# Generated by innovus_enablement/scripts/gen_fakeram.py: abstract 256x32 SRAM.
# Geometry is an assumption (see script header), not PDK data.
VERSION 5.8 ;
BUSBITCHARS "[]" ;
DIVIDERCHAR "/" ;

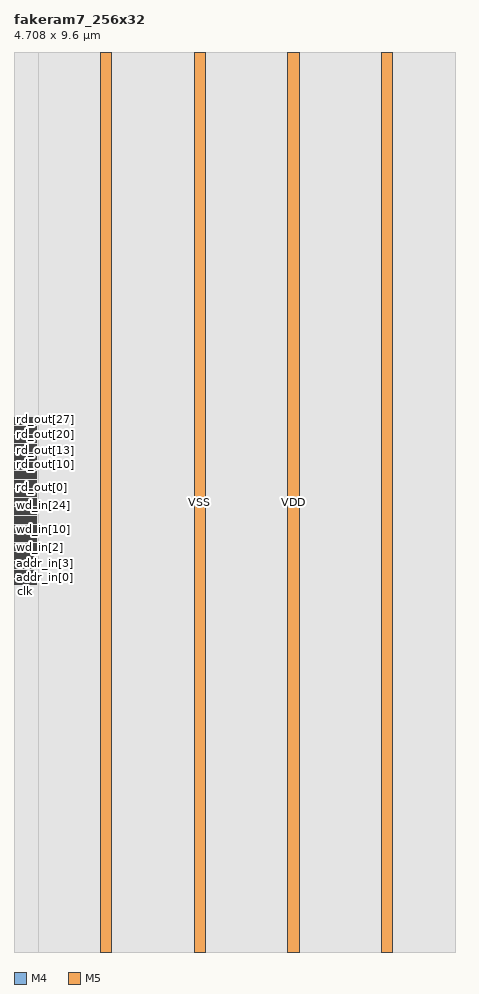
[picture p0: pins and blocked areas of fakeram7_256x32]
MACRO fakeram7_256x32
  CLASS BLOCK ;
  FOREIGN fakeram7_256x32 0 0 ;
  ORIGIN 0 0 ;
  SIZE 4.7080 BY 9.6000 ;
  SYMMETRY X Y R90 ;
  PIN clk
    DIRECTION INPUT ;
    USE CLOCK ;
    PORT
      LAYER M4 ;
        RECT 0 3.9180 0.2400 3.9300 ;
    END
  END clk
  PIN ce_in
    DIRECTION INPUT ;
    USE SIGNAL ;
    PORT
      LAYER M4 ;
        RECT 0 3.9420 0.2400 3.9540 ;
    END
  END ce_in
  PIN we_in
    DIRECTION INPUT ;
    USE SIGNAL ;
    PORT
      LAYER M4 ;
        RECT 0 3.9660 0.2400 3.9780 ;
    END
  END we_in
  PIN addr_in[0]
    DIRECTION INPUT ;
    USE SIGNAL ;
    PORT
      LAYER M4 ;
        RECT 0 3.9900 0.2400 4.0020 ;
    END
  END addr_in[0]
  PIN addr_in[1]
    DIRECTION INPUT ;
    USE SIGNAL ;
    PORT
      LAYER M4 ;
        RECT 0 4.0140 0.2400 4.0260 ;
    END
  END addr_in[1]
  PIN addr_in[2]
    DIRECTION INPUT ;
    USE SIGNAL ;
    PORT
      LAYER M4 ;
        RECT 0 4.0380 0.2400 4.0500 ;
    END
  END addr_in[2]
  PIN addr_in[3]
    DIRECTION INPUT ;
    USE SIGNAL ;
    PORT
      LAYER M4 ;
        RECT 0 4.0620 0.2400 4.0740 ;
    END
  END addr_in[3]
  PIN addr_in[4]
    DIRECTION INPUT ;
    USE SIGNAL ;
    PORT
      LAYER M4 ;
        RECT 0 4.0860 0.2400 4.0980 ;
    END
  END addr_in[4]
  PIN addr_in[5]
    DIRECTION INPUT ;
    USE SIGNAL ;
    PORT
      LAYER M4 ;
        RECT 0 4.1100 0.2400 4.1220 ;
    END
  END addr_in[5]
  PIN addr_in[6]
    DIRECTION INPUT ;
    USE SIGNAL ;
    PORT
      LAYER M4 ;
        RECT 0 4.1340 0.2400 4.1460 ;
    END
  END addr_in[6]
  PIN addr_in[7]
    DIRECTION INPUT ;
    USE SIGNAL ;
    PORT
      LAYER M4 ;
        RECT 0 4.1580 0.2400 4.1700 ;
    END
  END addr_in[7]
  PIN wd_in[0]
    DIRECTION INPUT ;
    USE SIGNAL ;
    PORT
      LAYER M4 ;
        RECT 0 4.1820 0.2400 4.1940 ;
    END
  END wd_in[0]
  PIN wd_in[1]
    DIRECTION INPUT ;
    USE SIGNAL ;
    PORT
      LAYER M4 ;
        RECT 0 4.2060 0.2400 4.2180 ;
    END
  END wd_in[1]
  PIN wd_in[2]
    DIRECTION INPUT ;
    USE SIGNAL ;
    PORT
      LAYER M4 ;
        RECT 0 4.2300 0.2400 4.2420 ;
    END
  END wd_in[2]
  PIN wd_in[3]
    DIRECTION INPUT ;
    USE SIGNAL ;
    PORT
      LAYER M4 ;
        RECT 0 4.2540 0.2400 4.2660 ;
    END
  END wd_in[3]
  PIN wd_in[4]
    DIRECTION INPUT ;
    USE SIGNAL ;
    PORT
      LAYER M4 ;
        RECT 0 4.2780 0.2400 4.2900 ;
    END
  END wd_in[4]
  PIN wd_in[5]
    DIRECTION INPUT ;
    USE SIGNAL ;
    PORT
      LAYER M4 ;
        RECT 0 4.3020 0.2400 4.3140 ;
    END
  END wd_in[5]
  PIN wd_in[6]
    DIRECTION INPUT ;
    USE SIGNAL ;
    PORT
      LAYER M4 ;
        RECT 0 4.3260 0.2400 4.3380 ;
    END
  END wd_in[6]
  PIN wd_in[7]
    DIRECTION INPUT ;
    USE SIGNAL ;
    PORT
      LAYER M4 ;
        RECT 0 4.3500 0.2400 4.3620 ;
    END
  END wd_in[7]
  PIN wd_in[8]
    DIRECTION INPUT ;
    USE SIGNAL ;
    PORT
      LAYER M4 ;
        RECT 0 4.3740 0.2400 4.3860 ;
    END
  END wd_in[8]
  PIN wd_in[9]
    DIRECTION INPUT ;
    USE SIGNAL ;
    PORT
      LAYER M4 ;
        RECT 0 4.3980 0.2400 4.4100 ;
    END
  END wd_in[9]
  PIN wd_in[10]
    DIRECTION INPUT ;
    USE SIGNAL ;
    PORT
      LAYER M4 ;
        RECT 0 4.4220 0.2400 4.4340 ;
    END
  END wd_in[10]
  PIN wd_in[11]
    DIRECTION INPUT ;
    USE SIGNAL ;
    PORT
      LAYER M4 ;
        RECT 0 4.4460 0.2400 4.4580 ;
    END
  END wd_in[11]
  PIN wd_in[12]
    DIRECTION INPUT ;
    USE SIGNAL ;
    PORT
      LAYER M4 ;
        RECT 0 4.4700 0.2400 4.4820 ;
    END
  END wd_in[12]
  PIN wd_in[13]
    DIRECTION INPUT ;
    USE SIGNAL ;
    PORT
      LAYER M4 ;
        RECT 0 4.4940 0.2400 4.5060 ;
    END
  END wd_in[13]
  PIN wd_in[14]
    DIRECTION INPUT ;
    USE SIGNAL ;
    PORT
      LAYER M4 ;
        RECT 0 4.5180 0.2400 4.5300 ;
    END
  END wd_in[14]
  PIN wd_in[15]
    DIRECTION INPUT ;
    USE SIGNAL ;
    PORT
      LAYER M4 ;
        RECT 0 4.5420 0.2400 4.5540 ;
    END
  END wd_in[15]
  PIN wd_in[16]
    DIRECTION INPUT ;
    USE SIGNAL ;
    PORT
      LAYER M4 ;
        RECT 0 4.5660 0.2400 4.5780 ;
    END
  END wd_in[16]
  PIN wd_in[17]
    DIRECTION INPUT ;
    USE SIGNAL ;
    PORT
      LAYER M4 ;
        RECT 0 4.5900 0.2400 4.6020 ;
    END
  END wd_in[17]
  PIN wd_in[18]
    DIRECTION INPUT ;
    USE SIGNAL ;
    PORT
      LAYER M4 ;
        RECT 0 4.6140 0.2400 4.6260 ;
    END
  END wd_in[18]
  PIN wd_in[19]
    DIRECTION INPUT ;
    USE SIGNAL ;
    PORT
      LAYER M4 ;
        RECT 0 4.6380 0.2400 4.6500 ;
    END
  END wd_in[19]
  PIN wd_in[20]
    DIRECTION INPUT ;
    USE SIGNAL ;
    PORT
      LAYER M4 ;
        RECT 0 4.6620 0.2400 4.6740 ;
    END
  END wd_in[20]
  PIN wd_in[21]
    DIRECTION INPUT ;
    USE SIGNAL ;
    PORT
      LAYER M4 ;
        RECT 0 4.6860 0.2400 4.6980 ;
    END
  END wd_in[21]
  PIN wd_in[22]
    DIRECTION INPUT ;
    USE SIGNAL ;
    PORT
      LAYER M4 ;
        RECT 0 4.7100 0.2400 4.7220 ;
    END
  END wd_in[22]
  PIN wd_in[23]
    DIRECTION INPUT ;
    USE SIGNAL ;
    PORT
      LAYER M4 ;
        RECT 0 4.7340 0.2400 4.7460 ;
    END
  END wd_in[23]
  PIN wd_in[24]
    DIRECTION INPUT ;
    USE SIGNAL ;
    PORT
      LAYER M4 ;
        RECT 0 4.7580 0.2400 4.7700 ;
    END
  END wd_in[24]
  PIN wd_in[25]
    DIRECTION INPUT ;
    USE SIGNAL ;
    PORT
      LAYER M4 ;
        RECT 0 4.7820 0.2400 4.7940 ;
    END
  END wd_in[25]
  PIN wd_in[26]
    DIRECTION INPUT ;
    USE SIGNAL ;
    PORT
      LAYER M4 ;
        RECT 0 4.8060 0.2400 4.8180 ;
    END
  END wd_in[26]
  PIN wd_in[27]
    DIRECTION INPUT ;
    USE SIGNAL ;
    PORT
      LAYER M4 ;
        RECT 0 4.8300 0.2400 4.8420 ;
    END
  END wd_in[27]
  PIN wd_in[28]
    DIRECTION INPUT ;
    USE SIGNAL ;
    PORT
      LAYER M4 ;
        RECT 0 4.8540 0.2400 4.8660 ;
    END
  END wd_in[28]
  PIN wd_in[29]
    DIRECTION INPUT ;
    USE SIGNAL ;
    PORT
      LAYER M4 ;
        RECT 0 4.8780 0.2400 4.8900 ;
    END
  END wd_in[29]
  PIN wd_in[30]
    DIRECTION INPUT ;
    USE SIGNAL ;
    PORT
      LAYER M4 ;
        RECT 0 4.9020 0.2400 4.9140 ;
    END
  END wd_in[30]
  PIN wd_in[31]
    DIRECTION INPUT ;
    USE SIGNAL ;
    PORT
      LAYER M4 ;
        RECT 0 4.9260 0.2400 4.9380 ;
    END
  END wd_in[31]
  PIN rd_out[0]
    DIRECTION OUTPUT ;
    USE SIGNAL ;
    PORT
      LAYER M4 ;
        RECT 0 4.9500 0.2400 4.9620 ;
    END
  END rd_out[0]
  PIN rd_out[1]
    DIRECTION OUTPUT ;
    USE SIGNAL ;
    PORT
      LAYER M4 ;
        RECT 0 4.9740 0.2400 4.9860 ;
    END
  END rd_out[1]
  PIN rd_out[2]
    DIRECTION OUTPUT ;
    USE SIGNAL ;
    PORT
      LAYER M4 ;
        RECT 0 4.9980 0.2400 5.0100 ;
    END
  END rd_out[2]
  PIN rd_out[3]
    DIRECTION OUTPUT ;
    USE SIGNAL ;
    PORT
      LAYER M4 ;
        RECT 0 5.0220 0.2400 5.0340 ;
    END
  END rd_out[3]
  PIN rd_out[4]
    DIRECTION OUTPUT ;
    USE SIGNAL ;
    PORT
      LAYER M4 ;
        RECT 0 5.0460 0.2400 5.0580 ;
    END
  END rd_out[4]
  PIN rd_out[5]
    DIRECTION OUTPUT ;
    USE SIGNAL ;
    PORT
      LAYER M4 ;
        RECT 0 5.0700 0.2400 5.0820 ;
    END
  END rd_out[5]
  PIN rd_out[6]
    DIRECTION OUTPUT ;
    USE SIGNAL ;
    PORT
      LAYER M4 ;
        RECT 0 5.0940 0.2400 5.1060 ;
    END
  END rd_out[6]
  PIN rd_out[7]
    DIRECTION OUTPUT ;
    USE SIGNAL ;
    PORT
      LAYER M4 ;
        RECT 0 5.1180 0.2400 5.1300 ;
    END
  END rd_out[7]
  PIN rd_out[8]
    DIRECTION OUTPUT ;
    USE SIGNAL ;
    PORT
      LAYER M4 ;
        RECT 0 5.1420 0.2400 5.1540 ;
    END
  END rd_out[8]
  PIN rd_out[9]
    DIRECTION OUTPUT ;
    USE SIGNAL ;
    PORT
      LAYER M4 ;
        RECT 0 5.1660 0.2400 5.1780 ;
    END
  END rd_out[9]
  PIN rd_out[10]
    DIRECTION OUTPUT ;
    USE SIGNAL ;
    PORT
      LAYER M4 ;
        RECT 0 5.1900 0.2400 5.2020 ;
    END
  END rd_out[10]
  PIN rd_out[11]
    DIRECTION OUTPUT ;
    USE SIGNAL ;
    PORT
      LAYER M4 ;
        RECT 0 5.2140 0.2400 5.2260 ;
    END
  END rd_out[11]
  PIN rd_out[12]
    DIRECTION OUTPUT ;
    USE SIGNAL ;
    PORT
      LAYER M4 ;
        RECT 0 5.2380 0.2400 5.2500 ;
    END
  END rd_out[12]
  PIN rd_out[13]
    DIRECTION OUTPUT ;
    USE SIGNAL ;
    PORT
      LAYER M4 ;
        RECT 0 5.2620 0.2400 5.2740 ;
    END
  END rd_out[13]
  PIN rd_out[14]
    DIRECTION OUTPUT ;
    USE SIGNAL ;
    PORT
      LAYER M4 ;
        RECT 0 5.2860 0.2400 5.2980 ;
    END
  END rd_out[14]
  PIN rd_out[15]
    DIRECTION OUTPUT ;
    USE SIGNAL ;
    PORT
      LAYER M4 ;
        RECT 0 5.3100 0.2400 5.3220 ;
    END
  END rd_out[15]
  PIN rd_out[16]
    DIRECTION OUTPUT ;
    USE SIGNAL ;
    PORT
      LAYER M4 ;
        RECT 0 5.3340 0.2400 5.3460 ;
    END
  END rd_out[16]
  PIN rd_out[17]
    DIRECTION OUTPUT ;
    USE SIGNAL ;
    PORT
      LAYER M4 ;
        RECT 0 5.3580 0.2400 5.3700 ;
    END
  END rd_out[17]
  PIN rd_out[18]
    DIRECTION OUTPUT ;
    USE SIGNAL ;
    PORT
      LAYER M4 ;
        RECT 0 5.3820 0.2400 5.3940 ;
    END
  END rd_out[18]
  PIN rd_out[19]
    DIRECTION OUTPUT ;
    USE SIGNAL ;
    PORT
      LAYER M4 ;
        RECT 0 5.4060 0.2400 5.4180 ;
    END
  END rd_out[19]
  PIN rd_out[20]
    DIRECTION OUTPUT ;
    USE SIGNAL ;
    PORT
      LAYER M4 ;
        RECT 0 5.4300 0.2400 5.4420 ;
    END
  END rd_out[20]
  PIN rd_out[21]
    DIRECTION OUTPUT ;
    USE SIGNAL ;
    PORT
      LAYER M4 ;
        RECT 0 5.4540 0.2400 5.4660 ;
    END
  END rd_out[21]
  PIN rd_out[22]
    DIRECTION OUTPUT ;
    USE SIGNAL ;
    PORT
      LAYER M4 ;
        RECT 0 5.4780 0.2400 5.4900 ;
    END
  END rd_out[22]
  PIN rd_out[23]
    DIRECTION OUTPUT ;
    USE SIGNAL ;
    PORT
      LAYER M4 ;
        RECT 0 5.5020 0.2400 5.5140 ;
    END
  END rd_out[23]
  PIN rd_out[24]
    DIRECTION OUTPUT ;
    USE SIGNAL ;
    PORT
      LAYER M4 ;
        RECT 0 5.5260 0.2400 5.5380 ;
    END
  END rd_out[24]
  PIN rd_out[25]
    DIRECTION OUTPUT ;
    USE SIGNAL ;
    PORT
      LAYER M4 ;
        RECT 0 5.5500 0.2400 5.5620 ;
    END
  END rd_out[25]
  PIN rd_out[26]
    DIRECTION OUTPUT ;
    USE SIGNAL ;
    PORT
      LAYER M4 ;
        RECT 0 5.5740 0.2400 5.5860 ;
    END
  END rd_out[26]
  PIN rd_out[27]
    DIRECTION OUTPUT ;
    USE SIGNAL ;
    PORT
      LAYER M4 ;
        RECT 0 5.5980 0.2400 5.6100 ;
    END
  END rd_out[27]
  PIN rd_out[28]
    DIRECTION OUTPUT ;
    USE SIGNAL ;
    PORT
      LAYER M4 ;
        RECT 0 5.6220 0.2400 5.6340 ;
    END
  END rd_out[28]
  PIN rd_out[29]
    DIRECTION OUTPUT ;
    USE SIGNAL ;
    PORT
      LAYER M4 ;
        RECT 0 5.6460 0.2400 5.6580 ;
    END
  END rd_out[29]
  PIN rd_out[30]
    DIRECTION OUTPUT ;
    USE SIGNAL ;
    PORT
      LAYER M4 ;
        RECT 0 5.6700 0.2400 5.6820 ;
    END
  END rd_out[30]
  PIN rd_out[31]
    DIRECTION OUTPUT ;
    USE SIGNAL ;
    PORT
      LAYER M4 ;
        RECT 0 5.6940 0.2400 5.7060 ;
    END
  END rd_out[31]
  PIN VDD
    DIRECTION INOUT ;
    USE POWER ;
    PORT
      LAYER M5 ;
        RECT 0.9200 0 1.0400 9.6000 ;
        RECT 2.9200 0 3.0400 9.6000 ;
    END
  END VDD
  PIN VSS
    DIRECTION INOUT ;
    USE GROUND ;
    PORT
      LAYER M5 ;
        RECT 1.9200 0 2.0400 9.6000 ;
        RECT 3.9200 0 4.0400 9.6000 ;
    END
  END VSS
  OBS
    LAYER M0 ;
      RECT 0 0 4.7080 9.6000 ;
    LAYER M1 ;
      RECT 0 0 4.7080 9.6000 ;
    LAYER M2 ;
      RECT 0 0 4.7080 9.6000 ;
    LAYER M3 ;
      RECT 0 0 4.7080 9.6000 ;
    LAYER VIA0 ;
      RECT 0 0 4.7080 9.6000 ;
    LAYER VIA1 ;
      RECT 0 0 4.7080 9.6000 ;
    LAYER VIA2 ;
      RECT 0 0 4.7080 9.6000 ;
    LAYER VIA3 ;
      RECT 0 0 4.7080 9.6000 ;
    LAYER M4 ;
      RECT 0.2640 0 4.7080 9.6000 ;
  END
END fakeram7_256x32

END LIBRARY
